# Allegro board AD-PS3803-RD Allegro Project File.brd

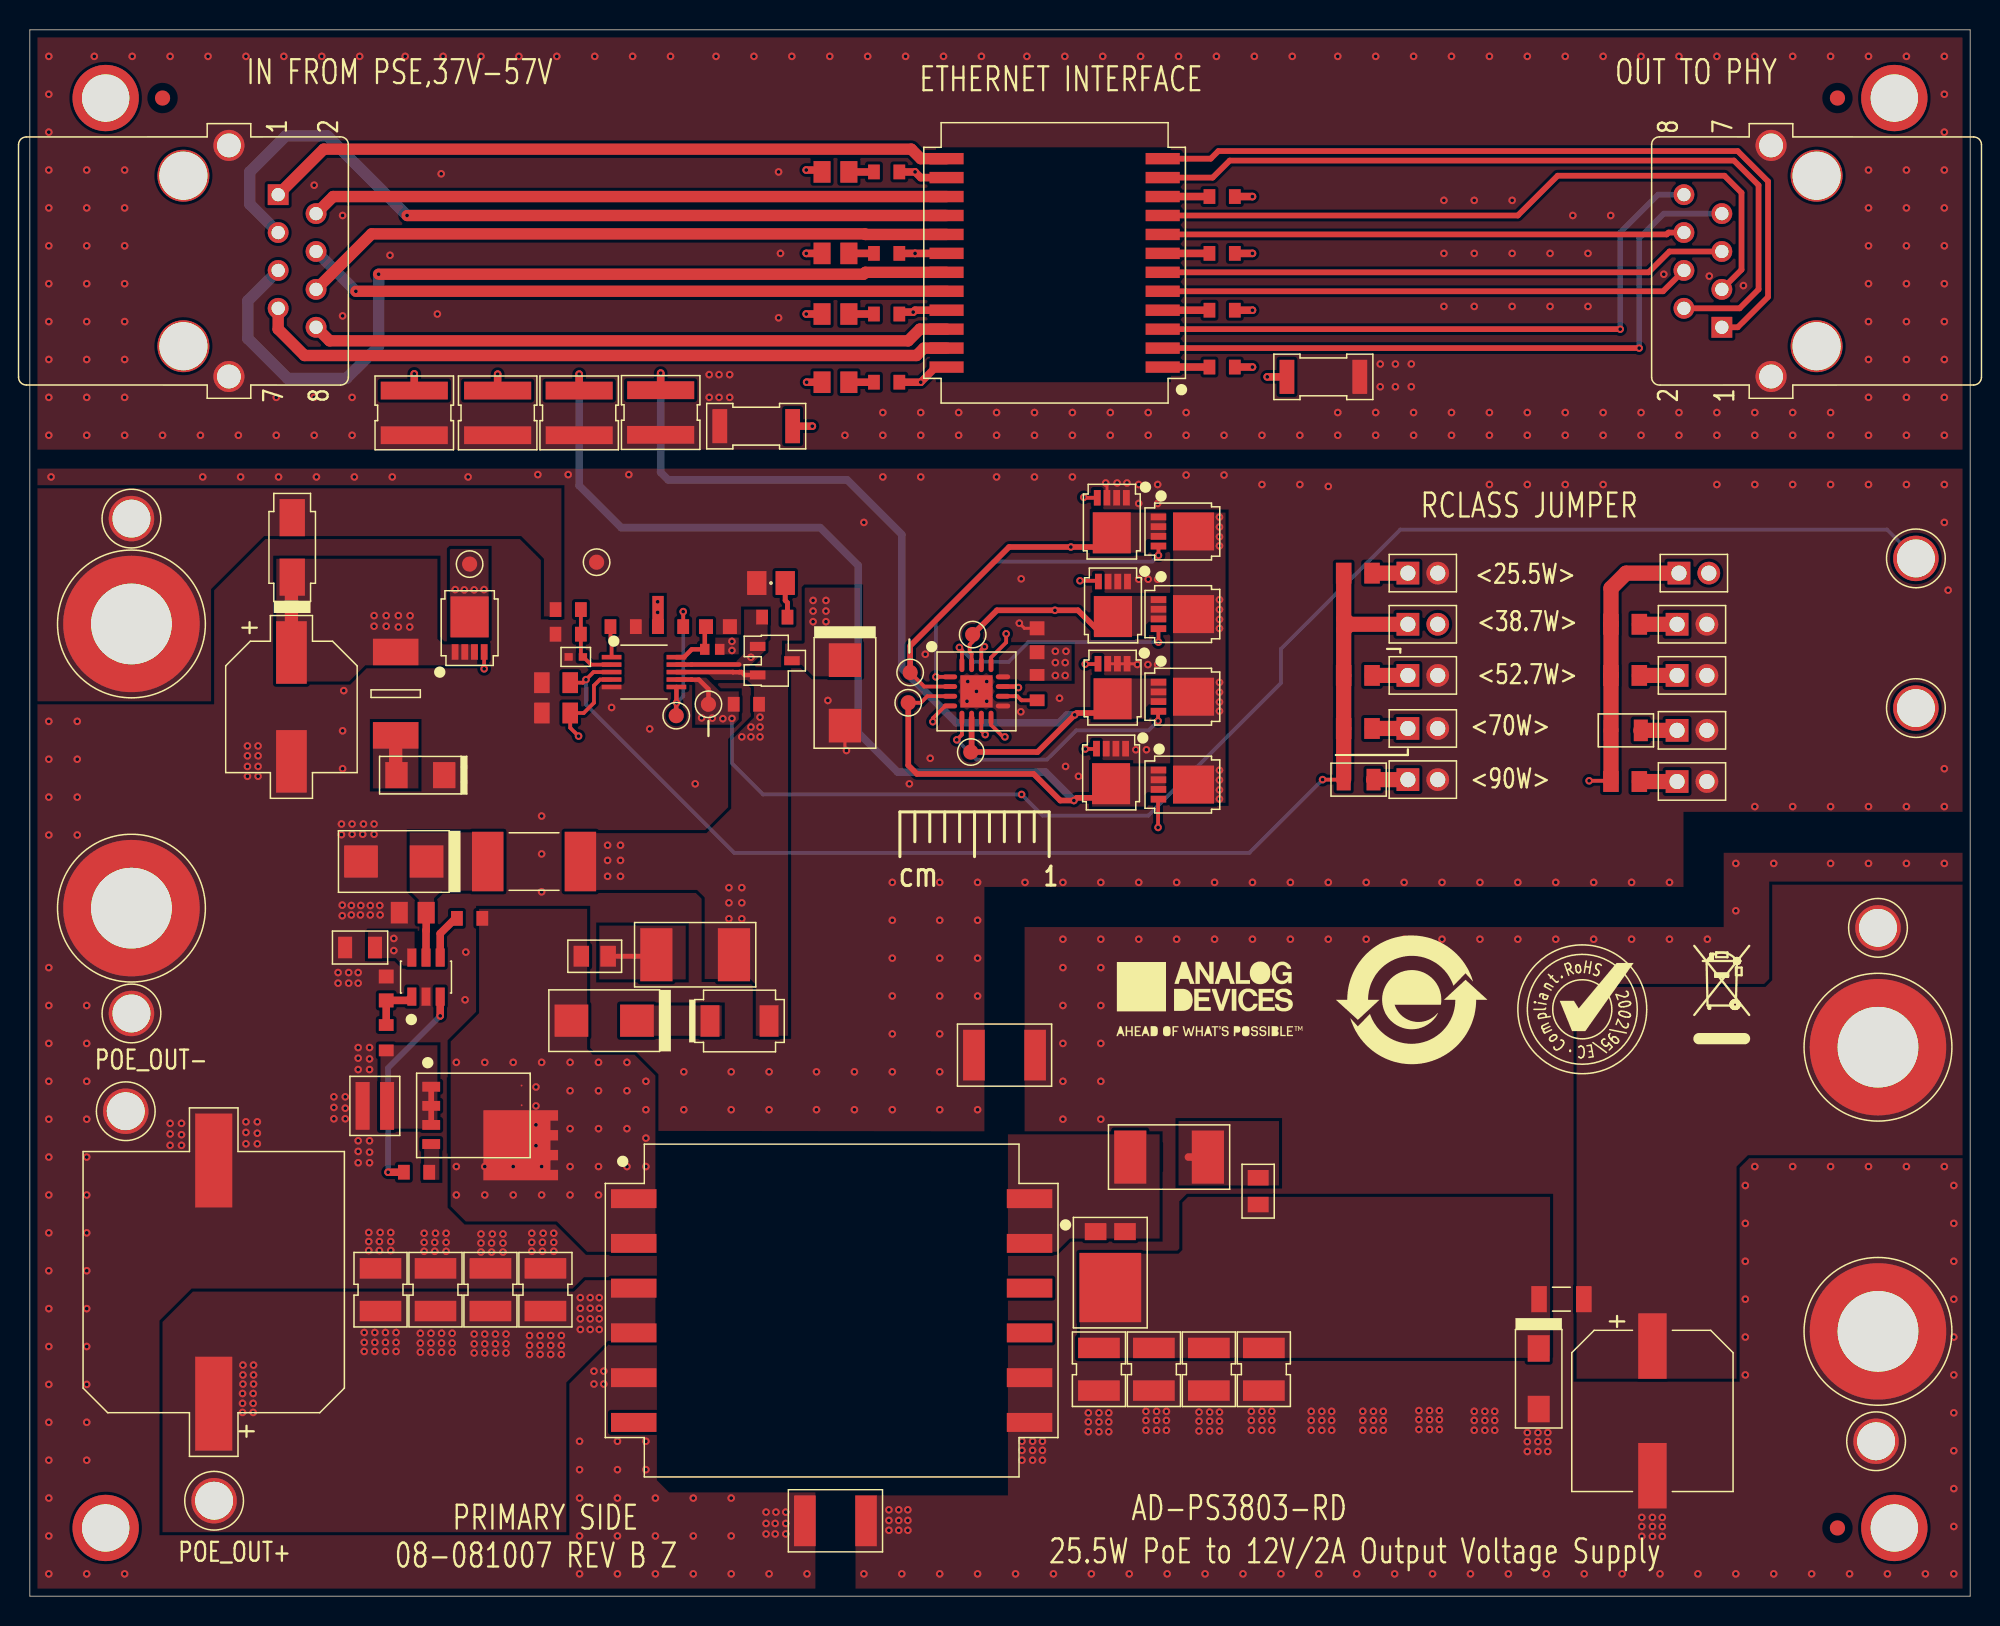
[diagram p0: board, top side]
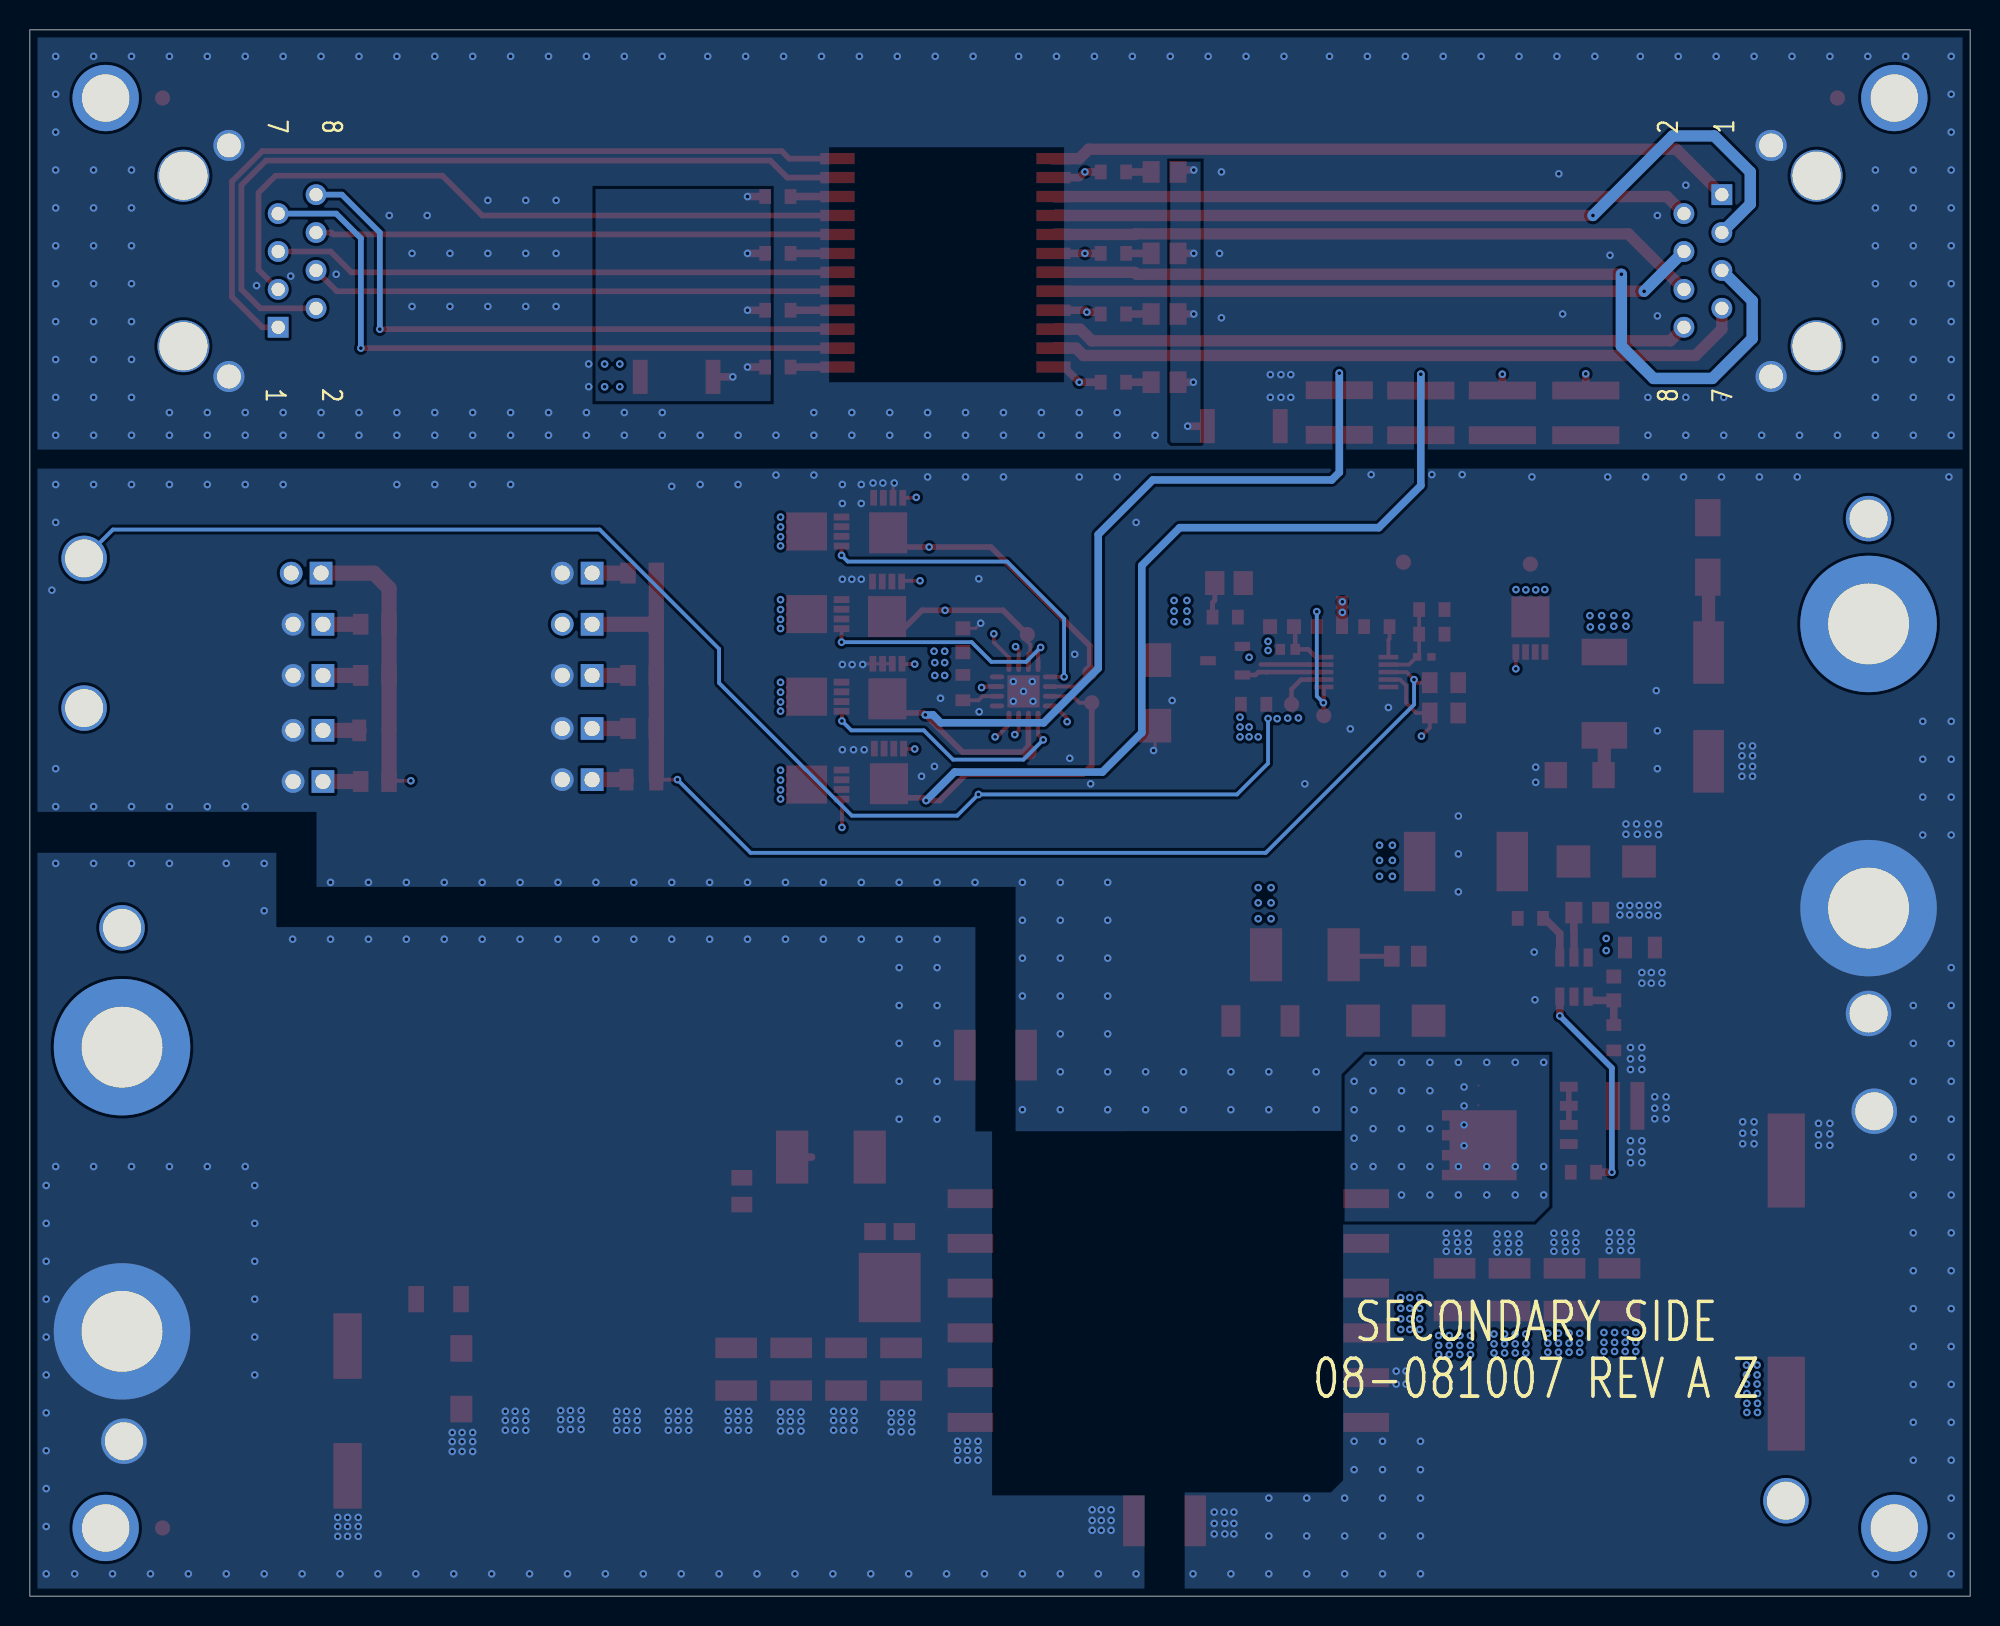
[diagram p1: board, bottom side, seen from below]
Outline 130 x 105 mm; copper layers: TOP, L2_GND, L3_PWR, BOTTOM. Coordinates in mm from the lower left corner of the outline.
Outline path: 0,105 0,0 130,0 130,105 0,105

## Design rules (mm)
constraint set DEFAULT: min track width 0.203

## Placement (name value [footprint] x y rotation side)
AUX+  575-4  [CNBANANAD312LD203]  6.81 65.17 0 top
AUX-  575-4  [CNBANANAD312LD203]  6.81 46.12 0 top
C1  0.047UF  [C0603]  67.49 64.08 90 top
C2  0.01uF  [C0402H22]  36.58 62.96 180 top
C3  0.047UF  [C0603]  46.1 65 180 top
C4  0.047uF  [C0805H60]  49.66 67.92 180 top
C5  22UF  [CPLSMSQ327H413]  17.53 59.61 270 top
C6  0.01UF  [C0805H55]  53.98 95.48 180 top
C7  0.01UF  [C0805H55]  53.98 90.01 180 top
C8  1000pF  [C1808H85]  48.67 78.43 180 top
C9  0.01UF  [C0805H55]  53.98 85.95 180 top
C10  0.01UF  [C0805H55]  53.98 81.38 180 top
C11  1000pF  [C1808H85]  86.66 81.74 0 top
C12  100uF  [CPLSMSQ669H669]  12.32 21.05 90 top
C13  10UF  [C1210H110]  23.49 20.55 90 top
C14  10UF  [C1210H110]  27.18 20.55 90 top
C15  10UF  [C1210H110]  30.86 20.55 90 top
C16  10UF  [C1210H110]  34.54 20.55 90 top
C17  1uF  [C0805]  25.65 45.82 180 top
C18  1000pF  [C0603]  23.88 40.74 90 top
C19  680PF  [C0805H30]  37.85 42.9 180 top
C20  2200pF  [C1812H100]  53.98 5.05 0 top
C21  22UF  [C1210H110]  71.63 15.21 270 top
C22  680PF  [C0805H30]  82.3 27.15 270 top
C23  22UF  [C1210H110]  75.31 15.21 270 top
C24  22UF  [C1210H110]  78.99 15.21 270 top
C25  22UF  [C1210H110]  82.68 15.21 270 top
C26  330UF  [CPLSMSQ406H500]  108.71 12.42 270 top
C35  2200pF  [C1812H100]  65.3 36.27 0 top
D1  SMBJ58A  [DO214AA_A]  54.61 60.55 270 top
D2  B1100-13-F  [SMA-2]  17.58 70.3 90 top
D3  SMBJ58A  [DO214AA_A]  24.38 49.25 180 top
D4  SMBJ28A-Q  [DO214AAH96]  47.55 38.56 0 top
D5  SDT5H100SB-13  [DO214AA_A]  38.48 38.58 180 top
D6  FSV1060V  [TO-277]  72.39 21.69 270 top
D7  CMZ5928B TR13 PBFREE  [DO214AC-2]  101.09 14.58 270 top
DS1  SML-LX1206GW-TR  [LEDSML126W63H43]  26.16 55.04 180 top
JP9  M22-2010205  [CNHDR1X2H207]  92.33 68.58 0 top
JP10  M22-2010205  [CNHDR1X2H207]  110.49 68.58 0 top
JP11  M22-2010205  [CNHDR1X2H207]  92.33 65.15 0 top
JP12  M22-2010205  [CNHDR1X2H207]  110.36 65.15 0 top
JP13  M22-2010205  [CNHDR1X2H207]  92.33 61.72 0 top
JP14  M22-2010205  [CNHDR1X2H207]  110.36 61.72 0 top
JP15  M22-2010205  [CNHDR1X2H207]  92.33 58.17 0 top
JP16  M22-2010205  [CNHDR1X2H207]  110.36 58.04 0 top
JP17  M22-2010205  [CNHDR1X2H207]  92.33 54.74 0 top
JP18  M22-2010205  [CNHDR1X2H207]  110.36 54.61 0 top
NOREF  -  []  78.74 40 0 top
NOREF#2  -  [unnamed#2]  5.08 4.57 0 top
NOREF#3  -  [unnamed#2]  124.92 100.43 0 top
NOREF#4  -  []  130 0 90 top
NOREF#5  -  [unnamed#2]  124.92 4.57 0 top
NOREF#6  -  []  35.18 0.35 270 top
NOREF#7  -  []  130 0.02 90 top
NOREF#8  -  [unnamed#2]  8.89 100.43 0 top
NOREF#9  -  []  0 104.36 0 top
NOREF#10  -  []  -14.6 -26.83 0 top
NOREF#11  -  []  58.29 52.57 0 top
NOREF#12  -  [unnamed#2]  5.08 100.43 0 top
NOREF#13  -  []  130 105 180 top
NOREF#14  -  []  104.01 39.34 0 top
NOREF#15  -  []  -222.25 -345.85 0 top
NOREF#16  -  []  0 105 270 top
NOREF#17  -  []  69.09 112.24 0 top
NOREF#18  -  []  113.16 37.06 0 top
NOREF#19  -  []  199.39 74.97 0 top
NOREF#20  -  []  0 0 0 top
NOREF#21  -  [unnamed#2]  121.11 4.57 0 top
NOREF#22  -  []  -222.25 -345.85 0 top
NOREF#23  -  []  -222.25 -345.85 0 top
NOREF#24  -  [unnamed#2]  121.11 100.43 0 top
NOREF#25  -  []  92.58 39.98 0 top
P1  SS-7188S-A-NF  [CNBELSS-7188S-A-NF]  16.64 93.95 270 top
P2  SS-7188S-A-NF  [CNBELSS-7188S-A-NF]  113.36 85.06 90 top
PWRGD  2501-2-00-80-00-00-07-0  [CNMILLMAX2501]  126.36 69.57 270 top
Q1  PSMN075-100MSEX  [SOT1210]  77.27 65.83 270 top
Q2  PSMN075-100MSEX  [SOT1210]  72.57 66.37 180 top
Q3  PSMN075-100MSEX  [SOT1210]  77.27 71.37 270 top
Q4  PSMN075-100MSEX  [SOT1210]  72.49 71.98 180 top
Q5  PSMN075-100MSEX  [SOT1210]  77.27 54.4 270 top
Q6  PSMN075-100MSEX  [SOT1210]  72.44 55.17 180 top
Q7  PSMN075-100MSEX  [SOT1210]  77.27 60.3 270 top
Q8  PSMN075-100MSEX  [SOT1210]  72.54 60.85 180 top
Q9  SI2328DS-T1-GE3  [SOT23_B]  49.91 62.71 270 top
Q10  PSMN040-100MSEX  [SOT1210]  29.46 64.94 0 top
Q11  BSC190N12NS3GATMA1  [SON8]  29.72 32.23 270 top
R1  0  [R0603]  67.49 60.91 90 top
R2  82.5K  [R0603]  36.07 66.14 0 top
R3  20K  [R0603]  36.07 64.49 180 top
R4  0  [R0603]  39.75 65 0 top
R5  34.8  [R0805]  35.26 61.24 180 top
R6  34.8  [R0805]  35.26 59.2 180 top
R7  8.2  [R0402]  45.72 63.47 180 top
R8  3.3K  [R0603]  49.91 65.63 0 top
R9  0  [R2512H35]  33.78 49.25 180 top
R10  100K  [R0603]  48.01 59.79 180 top
R11  100K  [R0603]  42.93 65 0 top
R12  4.7K  [R2512]  24.51 60.5 270 top
R13  SD4-90  [RSMSQ173H146]  42.27 79.35 270 top
R14  SD4-90  [RSMSQ173H146]  36.8 79.32 270 top
R15  SD4-90  [RSMSQ173H146]  31.34 79.32 270 top
R16  SD4-90  [RSMSQ173H146]  25.76 79.32 270 top
R17  75  [R0603]  57.4 95.48 180 top
R18  75  [R0603]  57.4 90.01 180 top
R19  75  [R0603]  57.4 85.95 180 top
R20  75  [R0603]  57.4 81.38 180 top
R21  75  [R0603]  79.88 82.39 0 top
R22  75  [R0603]  79.88 86.2 0 top
R23  75  [R0603]  79.88 90.01 0 top
R24  75  [R0603]  79.88 93.82 0 top
R28  34.8  [R0805]  88.98 68.58 0 top
R29  140  [R0805]  88.98 61.72 0 top
R30  76.8  [R0805]  88.98 58.17 0 top
R31  49.9  [R0805H20]  89.03 54.74 0 top
R32  34.8  [R0805]  106.88 65.15 180 top
R33  46.4  [R0805]  106.88 61.72 180 top
R34  64.9  [R0805H20]  106.93 58.04 180 top
R35  118  [R0805]  106.88 54.61 180 top
R36  4K  [R0805H20]  22.12 43.48 180 top
R37  237K  [R0603]  29.46 45.44 0 top
R38  17.8  [R2512H31]  44.58 43 180 top
R39  0  [R0603]  25.91 28.42 0 top
R40  0  [R0603]  23.88 37.44 270 top
R41  0.02  [R0612]  23.11 32.86 180 top
R42  17.8  [R2512H31]  76.33 29.44 0 top
R43  0  [R1206]  102.62 19.91 0 top
T1  7490220122  [TSML720W579H346]  68.66 89.38 90 top
TP1  TESTPAD  [TPSMC40]  63.17 64.46 270 top
TP2  TESTPAD  [TPSMC40]  58.98 61.92 270 top
TP3  TESTPAD  [TPSMC40]  58.85 59.89 270 top
TP4  TESTPAD  [TPSMC40]  63.04 56.59 270 top
TP5  2501-2-00-80-00-00-07-0  [CNMILLMAX2501]  6.81 72.23 0 top
TP6  2501-2-00-80-00-00-07-0  [CNMILLMAX2501]  6.81 39.06 0 top
TP7  TESTPAD  [TPSMC40]  43.31 59.03 180 top
TP8  TESTPAD  [TPSMC40]  45.47 59.79 180 top
TP14  2501-2-00-80-00-00-07-0  [CNMILLMAX2501]  12.34 6.4 180 top
TP15  2501-2-00-80-00-00-07-0  [CNMILLMAX2501]  6.43 32.51 270 top
TP16  2501-2-00-80-00-00-07-0  [CNMILLMAX2501]  123.83 44.8 180 top
TP17  2501-2-00-80-00-00-07-0  [CNMILLMAX2501]  123.7 10.39 90 top
U1  LT4321HUF#TRPBF  [QFN16_4X4_PAD2_15X2_15]  63.42 60.65 270 top
U2  LT4275AHMS#PBF  [RM10]  41.15 61.95 270 top
U3  LT8306RS6#TRMPBF  [TSOT23_6]  26.54 41.5 0 top
UNK~T2P  2501-2-00-80-00-00-07-0  [CNMILLMAX2501]  126.36 59.53 270 top
VOUT+  575-4  [CNBANANAD312LD203]  123.83 36.8 90 top
VOUT-  575-4  [CNBANANAD312LD203]  123.83 17.75 0 top
VPORT+  TESTPAD  [TPSMC40]  29.46 69.19 0 top
VPORT-  TESTPAD  [TPSMC40]  37.97 69.31 0 top
X1  750316116  [TSML969W858H450]  53.72 19.15 0 top

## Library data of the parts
AUX+ AUX- VOUT+ VOUT- = CNTP1P: Tolerance: N/A; User Part Number: UPN; alternate symbols: (CNBANANAD312LD203); part number: CNTP1P_TH-575-4,E012555,CNBANANAD312LD203; tolerance: N/A
C1 C3 = CAP: User Part Number: UPN; Tolerance: 10; alternate symbols: (C0603); part number: CAP_SM-0.047UF,100V,10,E045169,C0603; tolerance: 10
C2 = CAP: Tolerance: 10; User Part Number: UPN; alternate symbols: (C0402H22); part number: CAP_SM-0.01UF,100V,10,E018427,C0402H22; tolerance: 10
C4 = CAP: Tolerance: 10; User Part Number: UPN; alternate symbols: (C0805H60); part number: CAP_SM-0.047UF,100V,10,E030859,C0805H60; tolerance: 10
C5 = CAPP: User Part Number: UPN; Tolerance: 20; alternate symbols: (CPLSMSQ327H413); part number: CAPP_SM-22UF,100V,20,E046045,CPLSMSQ327H413; tolerance: 20
C6 C7 C9 C10 = CAP: User Part Number: UPN; Tolerance: 10; alternate symbols: (C0805H55); part number: CAP_SM-0.01UF,500V,10,E062934,C0805H55; tolerance: 10
C8 C11 = CAP: User Part Number: UPN; Tolerance: 10; alternate symbols: (C1808H85); part number: CAP_SM-1000PF,2000V,10,E033755,C1808H85; tolerance: 10
C12 = CAPP: User Part Number: UPN; Tolerance: 20; alternate symbols: (CPLSMSQ669H669); part number: CAPP_SM-100UF,100V,20,E029775,CPLSMSQ669H669; tolerance: 20
C13-C16 = CAP: Tolerance: 10; User Part Number: UPN; alternate symbols: (C1210H110); part number: CAP_SM-10UF,75V,10,E054052,C1210H110; tolerance: 10
C17 = CAP: User Part Number: UPN; Tolerance: 10; alternate symbols: (C0805); part number: CAP_SM-1UF,100V,10,E014208,C0805; tolerance: 10
C18 = CAP: User Part Number: UPN; Tolerance: 5; alternate symbols: (C0603); part number: CAP_SM-1000PF,50V,5,E007908,C0603; tolerance: 5
C19 C22 = CAP: Tolerance: 10; User Part Number: UPN; alternate symbols: (C0805H30); part number: CAP_SM-680PF,100V,10,E065750,C0805H30; tolerance: 10
C20 C35 = CAP: Tolerance: 10; User Part Number: UPN; alternate symbols: (C1812H100); part number: CAP_SM-2200PF,2000V,10,E025550,C1812H100; tolerance: 10
C21 C23-C25 = CAP: Tolerance: 10; User Part Number: UPN; alternate symbols: (C1210H110); part number: CAP_SM-22UF,25V,10,E063473,C1210H110; tolerance: 10
C26 = CAPP: Tolerance: 20; User Part Number: UPN; alternate symbols: (CPLSMSQ406H500); part number: CAPP_SM-330UF,25V,20,E046016,CPLSMSQ406H500; tolerance: 20
D1 D3 = DIOZNR: User Part Number: UPN; Tolerance: N/A; alternate symbols: (DO214AA_A); part number: DIOZNR_SM-SMBJ58A,58V,N/A,E036067,DO214AA_A; tolerance: N/A
D2 = DIOSCHOTTKY: User Part Number: UPN; Tolerance: N/A; alternate symbols: (SMA-2); part number: DIOSCHOTTKY_SM-B1100-13-F,100V,N/A,E026567,SMA-2; tolerance: N/A
D4 = DIOZNR: User Part Number: UPN; Tolerance: N/A; alternate symbols: (DO214AAH96); part number: DIOZNR_SM-SMBJ28A-Q,28V,N/A,E065782,DO214AAH96; tolerance: N/A
D5 = DIOSCHOTTKY: User Part Number: UPN; Tolerance: N/A; alternate symbols: (DO214AA_A); part number: DIOSCHOTTKY_SM-SDT5H100SB-13,100V,N/A,E057537,DO214AA_A; tolerance: N/A
D6 = DIOSCHOTTKY_3P: User Part Number: UPN; Tolerance: N/A; alternate symbols: (TO-277); part number: DIOSCHOTTKY_3P_SM-FSV1060V,60V,N/A,E044257,TO-277; tolerance: N/A
D7 = DIOZNR: User Part Number: UPN; Tolerance: 5; alternate symbols: (DO214AC-2); part number: DIOZNR_SM-CMZ5928B TR13 PBFREE,13V,5,E051593,DO214AC-2; tolerance: 5
DS1 = DIOLED: Tolerance: N/A; User Part Number: UPN; alternate symbols: (LEDSML126W63H43); part number: DIOLED_SM-SML-LX1206GW-TR,N/A,N/A,E008009,LEDSML126W63H43; tolerance: N/A
JP9-JP18 = CN2P: Tolerance: N/A; User Part Number: UPN; alternate symbols: (CNHDR1X2H207); part number: CN2P_TH-M22-2010205,E023091,CNHDR1X2H207; tolerance: N/A
P1 P2 = CN8P_2PSHLD: User Part Number: UPN; Tolerance: N/A; alternate symbols: (CNBELSS-7188S-A-NF); part number: CN8P_2PSHLD_TH-SS-7188S-A-NF,E053731,CNBELSS-7188S-A-NF; tolerance: N/A
PWRGD TP5 TP6 TP14-TP17 UNK~T2P = CNTP1P: User Part Number: UPN; Tolerance: N/A; alternate symbols: (CNMILLMAX2501); part number: CNTP1P_TH-2501-2-00-80-00-00-07-0,E031108,CNMILLMAX2501; tolerance: N/A
Q1-Q8 = TRANNMOSFET_V15: Tolerance: N/A; User Part Number: UPN; alternate symbols: (SOT1210); part number: TRANNMOSFET_V15_SM-PSMN075-100MSEX,E033196,SOT1210; tolerance: N/A
Q9 = TRANNMOSFET_V8: User Part Number: UPN; Tolerance: N/A; alternate symbols: (SOT23_B); part number: TRANNMOSFET_V8_SM-SI2328DS-T1-GE3,E051884,SOT23_B; tolerance: N/A
Q10 = TRANNMOSFET_V15: Tolerance: N/A; User Part Number: UPN; alternate symbols: (SOT1210); part number: TRANNMOSFET_V15_SM-PSMN040-100MSEX,E033197,SOT1210; tolerance: N/A
Q11 = TRANNMOSFET8P: Tolerance: N/A; User Part Number: UPN; alternate symbols: (SON8); part number: TRANNMOSFET8P_SM-BSC190N12NS3GATMA1,E063778,SON8; tolerance: N/A
R1 R4 R39 R40 = RES: User Part Number: UPN; Tolerance: JUMPER; alternate symbols: (R0603); part number: RES_SM-0,E007502,1/10W,JUMPER,R0603; tolerance: JUMPER
R2 = RES: User Part Number: UPN; Tolerance: 1; alternate symbols: (R0603); part number: RES_SM-82.5K,E045363,1/10W,1,R0603; tolerance: 1
R3 = RES: User Part Number: UPN; Tolerance: 1; alternate symbols: (R0603); part number: RES_SM-20K,E044318,1/10W,1,R0603; tolerance: 1
R5 R6 R28 R32 = RES: User Part Number: UPN; Tolerance: 1; alternate symbols: (R0805); part number: RES_SM-34.8,E050761,1/8W,1,R0805; tolerance: 1
R7 = RES: User Part Number: UPN; Tolerance: 5; alternate symbols: (R0402); part number: RES_SM-8.2,E057043,1/10W,5,R0402; tolerance: 5
R8 = RES: User Part Number: UPN; Tolerance: 1; alternate symbols: (R0603); part number: RES_SM-3.3K,E050689,1/10W,1,R0603; tolerance: 1
R9 = RES: User Part Number: UPN; Tolerance: JUMPER; alternate symbols: (R2512H35); part number: RES_SM-0,E050944,N/A,JUMPER,R2512H35; tolerance: JUMPER
R10 R11 = RES: User Part Number: UPN; Tolerance: 1; alternate symbols: (R0603); part number: RES_SM-100K,E010279,1/10W,1,R0603; tolerance: 1
R12 = RES: Tolerance: 1; User Part Number: UPN; alternate symbols: (R2512); part number: RES_SM-4.7K,E030605,1W,1,R2512; tolerance: 1
R13-R16 = RES: User Part Number: UPN; Tolerance: N/A; alternate symbols: (RSMSQ173H146); part number: RES_SM-SD4-90,E064608,N/A,N/A,RSMSQ173H146; tolerance: N/A
R17-R24 = RES: User Part Number: UPN; Tolerance: 1; alternate symbols: (R0603); part number: RES_SM-75,E003702,1/10W,1,R0603; tolerance: 1
R29 = RES: User Part Number: UPN; Tolerance: 1; alternate symbols: (R0805); part number: RES_SM-140,E003610,1/8W,1,R0805; tolerance: 1
R30 = RES: User Part Number: UPN; Tolerance: 1; alternate symbols: (R0805); part number: RES_SM-76.8,E045369,1/8W,1,R0805; tolerance: 1
R31 = RES: Tolerance: 1; User Part Number: UPN; alternate symbols: (R0805H20); part number: RES_SM-49.9,E039886,1/2W,1,R0805H20; tolerance: 1
R33 = RES: User Part Number: UPN; Tolerance: 1; alternate symbols: (R0805); part number: RES_SM-46.4,E003568,1/8W,1,R0805; tolerance: 1
R34 = RES: Tolerance: 1; User Part Number: UPN; alternate symbols: (R0805H20); part number: RES_SM-64.9,E064610,1/8W,1,R0805H20; tolerance: 1
R35 = RES: User Part Number: UPN; Tolerance: 1; alternate symbols: (R0805); part number: RES_SM-118,E045371,1/8W,1,R0805; tolerance: 1
R36 = RES: Tolerance: 1; User Part Number: UPN; alternate symbols: (R0805H20); part number: RES_SM-4K,E041265,1/8W,1,R0805H20; tolerance: 1
R37 = RES: User Part Number: UPN; Tolerance: 1; alternate symbols: (R0603); part number: RES_SM-237K,E044246,1/10W,1,R0603; tolerance: 1
R38 R42 = RES: User Part Number: UPN; Tolerance: 1; alternate symbols: (R2512H31); part number: RES_SM-17.8,E065749,1W,1,R2512H31; tolerance: 1
R41 = RES: User Part Number: UPN; Tolerance: 1; alternate symbols: (R0612); part number: RES_SM-0.02,E038131,1W,1,R0612; tolerance: 1
R43 = RES: User Part Number: UPN; Tolerance: 5; alternate symbols: (R1206); part number: RES_SM-0,E010093,1/4W,5,R1206; tolerance: 5
T1 = XFMR24P_V3: User Part Number: UPN; Tolerance: 2; alternate symbols: (TSML720W579H346); part number: XFMR24P_V3_SM-7490220122,E053759,TSML720W579H346; tolerance: 2
TP1-TP4 TP7 TP8 VPORT+ VPORT- = NCTESTPAD: Tolerance: N/A; User Part Number: UPN; alternate symbols: (TPSMC40); part number: NCTESTPAD_SM-TESTPAD,E019801,TPSMC40; tolerance: N/A
U1 = ICLT4321: User Part Number: UPN; Tolerance: N/A; alternate symbols: (QFN16_4X4_PAD2_15X2_15); part number: ICLT4321_SM-LT4321HUF#TRPBF,E033126,QFN16_4X4_PAD2_15X2_15; tolerance: N/A
U2 = ICLT4275: Tolerance: N/A; User Part Number: UPN; alternate symbols: (RM10); part number: ICLT4275_SM-LT4275AHMS#PBF,E033120,RM10; tolerance: N/A
U3 = ADLT8306: User Part Number: UPN; Tolerance: N/A; alternate symbols: (TSOT23_6); part number: ADLT8306_SM-LT8306RS6#TRMPBF,E063469,TSOT23_6; tolerance: N/A
X1 = XFMR12P_V21: User Part Number: UPN; Tolerance: N/A; alternate symbols: (TSML969W858H450); part number: XFMR12P_V21_SM-750316116,E064732,TSML969W858H450; tolerance: N/A

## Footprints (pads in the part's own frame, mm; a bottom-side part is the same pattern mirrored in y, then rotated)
C0402H22
  rect 0.559x0.508 smd: 1(-0.479,0) 2(0.479,0)
C0603
  rect 0.94x0.991 smd: 1(-0.8,0) 2(0.8,0)
C0805
  rect 1.143x1.448 smd: 1(-0.9,0) 2(0.9,0)
C0805H30
  rect 1.041x1.397 smd: 1(-0.9,0) 2(0.9,0)
C0805H55
  rect 1.143x1.448 smd: 1(-0.9,0) 2(0.9,0)
C0805H60
  rect 1.295x1.6 smd: 1(-0.953,0) 2(0.953,0)
C1210H110
  rect 1.372x2.794 smd: 1(-1.431,0) 2(1.431,0)
C1808H85
  rect 0.991x2.286 smd: 1(-2.44,0) 2(2.44,0)
C1812H100
  rect 1.448x3.404 smd: 1(-2.05,0) 2(2.05,0)
CNBANANAD312LD203
  round 9.144 hole 5.41: 1(0,0)
CNBELSS-7188S-A-NF
  round 3.48 hole 3.226 unplated: (-1.27,-6.35) (10.16,-6.35)
  rect 1.397x1.397 hole 0.889: 1(0,0)
  round 1.397 hole 0.889: 2(1.27,2.54) 3(2.54,0) 4(3.81,2.54) 5(5.08,0) 6(6.35,2.54) 7(7.62,0) 8(8.89,2.54)
  round 2.083 hole 1.6: 9(-3.3,-3.3) 10(12.19,-3.3)
CNHDR1X2H207
  rect 1.524x1.524 hole 1.016: 1(0,0)
  round 1.524 hole 1.016: 2(2,0)
CNMILLMAX2501
  round 3.048 hole 2.54: 1(0,0)
CPLSMSQ327H413
  rect 4.191x2.057 smd: N(3.65,0) P(-3.65,0)
CPLSMSQ406H500
  rect 4.394x1.905 smd: N(4.347,0) P(-4.347,0)
CPLSMSQ669H669
  rect 6.299x2.489 smd: N(8.15,0) P(-8.15,0)
DO214AA_A
  rect 2.261x2.159 smd: A(2.197,0) C(-2.197,0)
DO214AAH96
  rect 1.27x2.108 smd: A(1.98,0) C(-1.98,0)
DO214AC-2
  rect 1.778x1.473 smd: A(2.032,0) C(-2.032,0)
LEDSML126W63H43
  rect 1.499x1.753 smd: A(1.6,0) C(-1.6,0)
QFN16_4X4_PAD2_15X2_15
  oval 0.33x0.965 smd: 1(-0.975,-1.777) 2(-0.325,-1.777) 3(0.325,-1.777) 4(0.975,-1.777) 9(0.975,1.777) 10(0.325,1.777) 11(-0.325,1.777) 12(-0.975,1.777)
  oval 0.965x0.33 smd: 5(1.777,-0.975) 6(1.777,-0.325) 7(1.777,0.325) 8(1.777,0.975) 13(-1.777,0.975) 14(-1.777,0.325) 15(-1.777,-0.325) 16(-1.777,-0.975)
  rect 2.159x2.159 smd: PAD(0,0)
R0402
  rect 0.635x0.737 smd: 1(-0.5,0) 2(0.5,0)
R0603
  rect 0.787x0.991 smd: 1(-0.85,0) 2(0.85,0)
R0612
  rect 0.94x3.2 smd: 1(-0.82,0) 2(0.82,0)
R0805
  rect 1.041x1.397 smd: 1(-0.95,0) 2(0.95,0)
R0805H20
  rect 0.94x1.448 smd: 1(-1,0) 2(1,0)
R1206
  rect 1.041x1.753 smd: 1(-1.5,0) 2(1.5,0)
R2512
  rect 1.778x3.048 smd: 1(-2.794,0) 2(2.794,0)
R2512H31
  rect 2.159x3.556 smd: 1(-2.6,0) 2(2.6,0)
R2512H35
  rect 2.108x3.988 smd: 1(-3.104,0) 2(3.104,0)
RM10
  rect 0.305x1.321 smd: 1(-1,-2.171) 2(-0.5,-2.171) 3(0,-2.171) 4(0.5,-2.171) 5(1,-2.171) 6(1,2.171) 7(0.5,2.171) 8(0,2.171) 9(-0.5,2.171) 10(-1,2.171)
RSMSQ173H146
  rect 1.194x4.496 smd: 1(-1.497,0) 2(1.497,0)
SMA-2
  rect 2.489x1.702 smd: A(1.995,0) C(-1.995,0)
SON8
  rect 0.66x1.194 smd: 1(-1.92,-2.828) 2(-0.64,-2.828) 3(0.64,-2.828) 4(1.92,-2.828)
  custom 1.175x1.175 smd: 5(2,3.171)
  round 0.127 smd: 6(0.678,3.211) 7(-0.68,3.236) 8(-2.002,3.223)
SOT23_B
  rect 0.61x1.041 smd: 1(-0.958,-1.15) 2(0.958,-1.15) 3(0,1.15)
SOT1210
  rect 0.457x1.041 smd: 1(-0.975,-1.65) 2(-0.325,-1.65) 3(0.325,-1.65) 4(0.975,-1.65)
  round 0.127 smd: 5(0.975,1.65) 6(0.325,1.65) 7(-0.325,1.65) 8(-0.975,1.65)
TO-277
  rect 1.143x1.448 smd: 1(-2.75,-0.985) 2(-2.75,0.985)
  rect 4.648x4.14 smd: 3(1,0)
TPSMC40
  round 1.016 smd: 1(0,0)
TSML720W579H346
  rect 0.762x2.286 smd: 1(-6.985,-7.24) 2(-5.715,-7.24) 3(-4.445,-7.24) 4(-3.175,-7.24) 5(-1.905,-7.24) 6(-0.635,-7.24) 7(0.635,-7.24) 8(1.905,-7.24) 9(3.175,-7.24) 10(4.445,-7.24) 11(5.715,-7.24) 12(6.985,-7.24) 13(6.985,7.24) 14(5.715,7.24) 15(4.445,7.24) 16(3.175,7.24) 17(1.905,7.24) 18(0.635,7.24) 19(-0.635,7.24) 20(-1.905,7.24) 21(-3.175,7.24) 22(-4.445,7.24) 23(-5.715,7.24) 24(-6.985,7.24)
TSML969W858H450
  rect 3.048x1.27 smd: 1(-13.26,7.5) 2(-13.26,4.5) 3(-13.26,1.5) 4(-13.26,-1.5) 5(-13.26,-4.5) 6(-13.26,-7.5) 7(13.26,-7.5) 8(13.26,-4.5) 9(13.26,-1.5) 10(13.26,1.5) 11(13.26,4.5) 12(13.26,7.5)
TSOT23_6
  rect 0.61x1.219 smd: 1(-0.95,-1.31) 2(0,-1.31) 3(0.95,-1.31) 4(0.95,1.31) 5(0,1.31) 6(-0.95,1.31)
unnamed#2
  round 4.445 hole 3.175 unplated: (0,0)

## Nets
GND_EARTH: C8.2(N2) C11.2(N2) P1.9 P1.10 P2.9 P2.10 R13.2(N2) R14.2(N2) R15.2(N2) R16.2(N2)
GND_ISO: C20.2(N2) C21.2(N2) C23.2(N2) C24.2(N2) C25.2(N2) C26.N(N2) C35.2(N2) D7.A(P) TP17.1(N1) VOUT-.1(N1) X1.7 X1.8
PGND: AUX-.1(N1) C1.2(N2) C2.2(N2) C3.1 C4.2(N2) C5.N(N2) C12.N(N2) C13.2(N2) C14.2(N2) C15.2(N2) C16.2(N2) C17.2(N2) C18.2(N2) C20.1 C35.1 D1.A(P) D3.A(P) DS1.C JP9.2(N2) JP12.2(N2) JP13.2(N2) JP14.2(N2) JP15.2(N2) JP16.2(N2) JP17.2(N2) JP18.2(N2) Q2.1 Q2.2 Q2.3(S3) Q4.1 Q4.2 Q4.3(S3) Q6.1 Q6.2 Q6.3(S3) Q8.1 Q8.2 Q8.3(S3) R3.2(N2) R4.2(N2) R5.2(N2) R6.2(N2) R36.2(N2) R41.2(N2) TP6.1(N1) TP15.1(N1) U1.9 U1.PAD U2.5 U3.2 VPORT-.1(N1) X1.5
BG12: Q2.4 U1.14
BG36: Q4.4 U1.13
BG45: Q6.4 U1.8
BG78: Q8.4 U1.7
DATA1: Q1.1 Q1.2 Q1.3(S3) Q2.5 Q2.6 Q2.7 Q2.8 R16.1 R17.1 T1.14 TP1.1(N1) U1.15
DATA2: Q3.1 Q3.2 Q3.3(S3) Q4.5 Q4.6 Q4.7 Q4.8 R15.1 R18.1 T1.18 TP2.1(N1) U1.2
POE_OUT+: C5.P C12.P C13.1 C14.1 C15.1 C16.1 D2.C D4.A(P) Q9.2(S) Q10.1 Q10.2 Q10.3(S3) R9.1 R10.1 R11.1 R12.1 R38.1 TP14.1(N1) U2.8 X1.3 X1.4
PWRGD: PWRGD.1(N1) R10.2(N2) R36.1 TP8.1(N1) U1.11 U2.7 U3.6
RCLASS: JP11.1 R5.1 R28.1 R29.1 R30.1 R31.1 U2.3
RCLASS++: JP10.1 R6.1 R32.2(N2) R33.2(N2) R34.2(N2) R35.2(N2) U2.4
SPARE1: Q5.1 Q5.2 Q5.3(S3) Q6.5 Q6.6 Q6.7 Q6.8 R14.1 R19.1 T1.21 TP3.1(N1) U1.3
SPARE2: Q7.1 Q7.2 Q7.3(S3) Q8.5 Q8.6 Q8.7 Q8.8 R13.1 R20.1 T1.24 TP4.1(N1) U1.6
TG12: Q1.4 U1.16
TG36: Q3.4 U1.1
TG45: Q5.4 U1.4
TG78: Q7.4 U1.5(TG78)
UNNAMED_3_CAP_I58_N1: C6.1 R17.2(N2)
UNNAMED_3_CAP_I58_N2: C6.2(N2) C7.2(N2) C8.1 C9.2(N2) C10.2(N2)
UNNAMED_3_CAP_I62_N1: C7.1 R18.2(N2)
UNNAMED_3_CAP_I63_N1: C9.1 R19.2(N2)
UNNAMED_3_CAP_I66_N1: C10.1 R20.2(N2)
UNNAMED_3_CAP_I72_N1: C11.1 R21.2(N2) R22.2(N2) R23.2(N2) R24.2(N2)
UNNAMED_3_CN8P2PSHLD_I51_N1: P1.1 T1.13
UNNAMED_3_CN8P2PSHLD_I51_N2: P1.2 T1.15
UNNAMED_3_CN8P2PSHLD_I51_N3: P1.3 T1.16
UNNAMED_3_CN8P2PSHLD_I51_N4: P1.4 T1.20
UNNAMED_3_CN8P2PSHLD_I51_N5: P1.5 T1.19
UNNAMED_3_CN8P2PSHLD_I51_N6: P1.6 T1.17
UNNAMED_3_CN8P2PSHLD_I51_N7: P1.7 T1.23
UNNAMED_3_CN8P2PSHLD_I51_N8: P1.8(N8) T1.22
UNNAMED_3_CN8P2PSHLD_I76_N1: P2.1 T1.12(TD4-)
UNNAMED_3_CN8P2PSHLD_I76_N2: P2.2 T1.11
UNNAMED_3_CN8P2PSHLD_I76_N3: P2.3 T1.9
UNNAMED_3_CN8P2PSHLD_I76_N4: P2.4 T1.5
UNNAMED_3_CN8P2PSHLD_I76_N5: P2.5 T1.6
UNNAMED_3_CN8P2PSHLD_I76_N6: P2.6 T1.8
UNNAMED_3_CN8P2PSHLD_I76_N7: P2.7 T1.2
UNNAMED_3_CN8P2PSHLD_I76_N8: P2.8(N8) T1.3
UNNAMED_3_ICLT4321_I6_ENN: R1.1 U1.10
UNNAMED_3_RES_I69_N1: R21.1 T1.1
UNNAMED_3_RES_I70_N1: R22.1 T1.4
UNNAMED_3_RES_I73_N1: R23.1 T1.7
UNNAMED_3_RES_I74_N1: R24.1 T1.10
UNNAMED_4_CAP_I7_N2: C3.2(N2) R7.2(N2) U2.10(VPORT)
UNNAMED_4_CAP_I43_N1: C2.1 R2.2(N2) R3.1 U2.2
UNNAMED_4_CAP_I58_N1: C4.1 R8.2(N2)
UNNAMED_4_CN2P_I91_N1: JP17.1 R31.2(N2)
UNNAMED_4_CN2P_I92_N1: JP15.1 R30.2(N2)
UNNAMED_4_CN2P_I93_N1: JP18.1 R35.1
UNNAMED_4_CN2P_I94_N1: JP16.1 R34.1
UNNAMED_4_CN2P_I97_N1: JP13.1 R29.2(N2)
UNNAMED_4_CN2P_I99_N1: JP14.1 R33.1
UNNAMED_4_CN2P_I100_N1: JP12.1 R32.1
UNNAMED_4_CN2P_I101_N1: JP9.1 R28.2(N2)
UNNAMED_4_CNTP1P_I36_N1: R11.2(N2) TP7.1(N1) U2.6 UNK~T2P.1
UNNAMED_4_DIOLED_I15_P: DS1.A(P) R12.2(N2)
UNNAMED_4_DIOSCHOTTKY_I5_P: AUX+.1(N1) D2.A(P) R2.1 TP5.1(N1)
UNNAMED_4_ICLT4275_I46_HSGATE: Q9.1 Q10.4 R8.1 U2.9
UNNAMED_4_ICLT4275_I46_IEEEUVLON: R4.1 U2.1
UNNAMED_7_ADLT8306_I16_GATE: R39.1 U3.3
UNNAMED_7_ADLT8306_I16_RFB: R37.1 U3.4
UNNAMED_7_ADLT8306_I16_SENSE: C18.1 R40.1 U3.1
UNNAMED_7_ADLT8306_I16_VIN: C17.1 D3.C R9.2(N2) U3.5(VIN)
UNNAMED_7_CAP_I31_N1: C19.1 R38.2(N2)
UNNAMED_7_CAP_I31_N2: C19.2(N2) D5.A(P) Q11.5 Q11.6 Q11.7 Q11.8 R37.2(N2) X1.1 X1.2
UNNAMED_7_CAP_I39_N1: C21.1 C22.2(N2) C23.1 C24.1 C25.1 D6.3(C) D7.C R43.1
UNNAMED_7_CAP_I61_N1: C22.1 R42.2(N2)
UNNAMED_7_CAPP_I46_N1: C26.P R43.2(N2) TP16.1(N1) VOUT+.1(N1)
UNNAMED_7_DIOSCHOTTKY3P_I36_A1: D6.1 D6.2 R42.1 X1.11 X1.12
UNNAMED_7_DIOSCHOTTKY_I29_N: D4.C D5.C
UNNAMED_7_RES_I24_N2: Q11.1 Q11.2 Q11.3(S3) R40.2(N2) R41.1
UNNAMED_7_RES_I25_N2: Q11.4 R39.2(N2)
VPORTP: C1.1 D1.C Q1.5 Q1.6 Q1.7 Q1.8 Q3.5 Q3.6 Q3.7 Q3.8 Q5.5 Q5.6 Q5.7 Q5.8 Q7.5 Q7.6 Q7.7 Q7.8 Q9.3 Q10.5 Q10.6 Q10.7 Q10.8 R1.2(N2) R7.1 U1.12 VPORT+.1(N1)

Pads without a net: JP10 2; JP11 2; X1 6 9 10

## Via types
v1: diameter 0.508, hole 0.254, TOP to BOTTOM, 932 vias

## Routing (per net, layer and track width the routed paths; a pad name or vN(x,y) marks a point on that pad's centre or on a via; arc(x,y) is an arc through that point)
GND_EARTH:
  vias: v1(1.27,103.22) v1(1.27,100.68) v1(1.27,98.14) v1(1.27,95.6) v1(1.27,93.06) v1(1.27,90.52) v1(1.27,87.98) v1(1.27,85.44) v1(1.27,82.9) v1(1.27,80.36) v1(1.27,77.82) v1(3.81,95.6) v1(3.81,93.06) v1(3.81,90.52) v1(3.81,87.98) v1(3.81,85.44) v1(3.81,82.9) v1(3.81,80.36) v1(3.81,77.82) v1(4.32,103.22) v1(6.35,95.6) v1(6.35,93.06) v1(6.35,90.52) v1(6.35,87.98) v1(6.35,85.44) v1(6.35,82.9) v1(6.35,80.36) v1(6.35,77.82) v1(6.86,103.22) v1(8.89,77.82) v1(9.4,103.22) v1(11.43,77.82) v1(11.94,103.22) v1(13.97,77.82) v1(14.48,103.22) v1(16.51,80.36) v1(16.51,77.82) v1(17.02,103.22) v1(19.05,94.59) v1(19.05,80.36) v1(19.05,77.82) v1(19.56,103.22) v1(20.95,92.55) v1(20.95,85.82) v1(21.59,80.36) v1(21.59,77.82) v1(22.1,103.22) v1(24.13,89.89) v1(25.15,103.22) v1(27.3,85.95) v1(27.56,95.35) v1(27.69,103.22) v1(30.23,103.22) v1(32.77,103.22) v1(35.31,103.22) v1(37.85,103.22) v1(40.39,103.22) v1(42.93,103.22) v1(45.52,81.89) v1(45.52,80.36) v1(45.97,103.22) v1(46.18,81.89) v1(46.18,80.36) v1(46.89,81.89) v1(46.89,80.36) v1(48.51,103.22) v1(50.16,95.48) v1(50.16,85.7) v1(50.29,90.01) v1(51.05,103.22) v1(53.59,103.22) v1(54.61,77.82) v1(56.13,103.22) v1(57.15,79.35) v1(57.15,77.82) v1(58.67,103.22) v1(59.69,79.35) v1(59.69,77.82) v1(61.21,103.22) v1(62.23,79.35) v1(62.23,77.82) v1(63.75,103.22) v1(64.77,79.35) v1(64.77,77.82) v1(66.8,103.22) v1(67.31,79.35) v1(67.31,77.82) v1(69.34,103.22) v1(69.85,79.35) v1(69.85,77.82) v1(71.88,103.22) v1(72.39,79.35) v1(72.39,77.82) v1(74.42,103.22) v1(74.93,79.35) v1(74.93,77.82) v1(76.96,103.22) v1(77.47,79.35) v1(77.47,77.82) v1(79.5,103.22) v1(80.01,77.82) v1(82.04,103.22) v1(82.55,77.82) v1(84.58,103.22) v1(85.09,77.82) v1(87.63,103.22) v1(87.63,79.35) v1(87.63,77.82) v1(90.17,103.22) v1(90.17,79.35) v1(90.17,77.82) v1(90.47,82.6) v1(90.47,81.07) v1(91.49,82.6) v1(91.49,81.07) v1(92.56,82.6) v1(92.56,81.08) v1(92.71,103.22) v1(92.71,79.35) v1(92.71,77.82) v1(94.74,93.57) v1(94.74,90.01) v1(94.74,86.46) v1(95.25,103.22) v1(95.25,79.35) v1(95.25,77.82) v1(96.77,93.57) v1(96.77,90.01) v1(96.77,86.46) v1(97.79,103.22) v1(97.79,79.35) v1(97.79,77.82) v1(99.31,93.57) v1(99.31,90.01) v1(99.31,86.46) v1(100.33,103.22) v1(100.33,79.35) v1(100.33,77.82) v1(101.85,90.01) v1(101.85,86.46) v1(102.87,103.22) v1(102.87,79.35) v1(102.87,77.82) v1(103.38,92.55) v1(104.39,90.01) v1(104.39,86.46) v1(105.41,103.22) v1(105.41,79.35) v1(105.41,77.82) v1(105.92,92.55) v1(107.95,103.22) v1(107.95,79.35) v1(107.95,77.82) v1(109.47,88.62) v1(110.49,103.22) v1(110.49,79.35) v1(110.49,77.82) v1(112.52,88.49) v1(113.03,103.22) v1(113.03,79.35) v1(113.03,77.82) v1(114.81,87.86) v1(115.57,103.22) v1(115.57,79.35) v1(115.57,77.82) v1(118.11,103.22) v1(118.11,79.35) v1(118.11,77.82) v1(120.65,103.22) v1(120.65,79.35) v1(120.65,77.82) v1(123.19,103.22) v1(123.19,95.6) v1(123.19,93.06) v1(123.19,90.52) v1(123.19,87.98) v1(123.19,85.44) v1(123.19,82.9) v1(123.19,80.36) v1(123.19,77.82) v1(125.73,103.22) v1(125.73,95.6) v1(125.73,93.06) v1(125.73,90.52) v1(125.73,87.98) v1(125.73,85.44) v1(125.73,82.9) v1(125.73,80.36) v1(125.73,77.82) v1(128.27,103.22) v1(128.27,100.68) v1(128.27,98.14) v1(128.27,95.6) v1(128.27,93.06) v1(128.27,90.52) v1(128.27,87.98) v1(128.27,85.44) v1(128.27,82.9) v1(128.27,80.36) v1(128.27,77.82)
GND_ISO:
  vias: v1(55.88,1.5) v1(57.56,5.79) v1(57.56,5.08) v1(57.56,4.42) v1(58.22,5.79) v1(58.22,5.08) v1(58.22,4.42) v1(58.42,1.5) v1(58.83,5.79) v1(58.83,5.08) v1(58.83,4.42) v1(60.96,1.5) v1(63.5,1.5) v1(66.04,1.5) v1(66.47,10.39) v1(66.47,9.78) v1(66.47,9.12) v1(67.18,10.39) v1(67.18,9.78) v1(67.18,9.12) v1(67.84,10.39) v1(67.84,9.78) v1(67.84,9.12) v1(68.58,1.5) v1(69.22,44.04) v1(69.22,42.14) v1(69.22,39.6) v1(69.22,37.06) v1(69.22,34.52) v1(69.22,31.98) v1(70.92,12.29) v1(70.92,11.68) v1(70.92,11.02) v1(71.12,1.5) v1(71.63,12.29) v1(71.63,11.68) v1(71.63,11.02) v1(71.75,44.04) v1(71.75,42.14) v1(71.75,39.6) v1(71.75,37.06) v1(71.75,34.52) v1(71.75,31.98) v1(72.29,12.29) v1(72.29,11.68) v1(72.29,11.02) v1(73.66,1.5) v1(74.3,44.04) v1(74.78,12.39) v1(74.78,11.78) v1(74.78,11.12) v1(75.49,12.39) v1(75.49,11.78) v1(75.49,11.12) v1(76.15,12.39) v1(76.15,11.78) v1(76.15,11.12) v1(76.2,1.5) v1(76.83,44.04) v1(78.33,12.34) v1(78.33,11.73) v1(78.33,11.07) v1(78.74,1.5) v1(79.04,12.34) v1(79.04,11.73) v1(79.04,11.07) v1(79.38,44.04) v1(79.71,12.34) v1(79.71,11.73) v1(79.71,11.07) v1(81.28,1.5) v1(81.91,44.04) v1(81.84,12.39) v1(81.84,11.78) v1(81.84,11.12) v1(82.55,12.39) v1(82.55,11.78) v1(82.55,11.12) v1(83.21,12.39) v1(83.21,11.78) v1(83.21,11.12) v1(83.82,1.5) v1(84.45,44.04) v1(85.85,12.39) v1(85.85,11.78) v1(85.85,11.12) v1(86.36,1.5) v1(86.56,12.39) v1(86.56,11.78) v1(86.56,11.12) v1(87,44.04) v1(87.22,12.39) v1(87.22,11.78) v1(87.22,11.12) v1(88.9,1.5) v1(89.31,12.39) v1(89.31,11.78) v1(89.31,11.12) v1(89.53,44.04) v1(90.02,12.39) v1(90.02,11.78) v1(90.02,11.12) v1(90.68,12.39) v1(90.68,11.78) v1(90.68,11.12) v1(91.44,1.5) v1(92.08,44.04) v1(93.07,12.44) v1(93.07,11.83) v1(93.07,11.17) v1(93.78,12.44) v1(93.78,11.83) v1(93.78,11.17) v1(93.98,1.5) v1(94.44,12.44) v1(94.44,11.83) v1(94.44,11.17) v1(94.61,44.04) v1(96.52,1.5) v1(96.77,12.39) v1(96.77,11.78) v1(96.77,11.12) v1(97.16,44.04) v1(97.49,12.39) v1(97.49,11.78) v1(97.49,11.12) v1(98.15,12.39) v1(98.15,11.78) v1(98.15,11.12) v1(99.06,1.5) v1(99.69,44.04) v1(100.33,10.97) v1(100.33,10.36) v1(100.33,9.7) v1(101.04,10.97) v1(101.04,10.36) v1(101.04,9.7) v1(101.6,1.5) v1(101.7,10.97) v1(101.7,10.36) v1(101.7,9.7) v1(102.23,44.04) v1(104.14,1.5) v1(104.77,44.04) v1(106.68,1.5) v1(107.31,44.04) v1(108,5.28) v1(108,4.67) v1(108,4.01) v1(108.71,5.28) v1(108.71,4.67) v1(108.71,4.01) v1(109.22,1.5) v1(109.37,5.28) v1(109.37,4.67) v1(109.37,4.01) v1(109.86,44.04) v1(111.76,1.5) v1(112.39,44.04) v1(114.3,49.12) v1(114.3,45.95) v1(114.3,1.5) v1(114.94,27.53) v1(114.94,24.99) v1(114.94,22.45) v1(114.94,19.91) v1(114.94,17.37) v1(114.94,14.83) v1(115.57,28.8) v1(116.84,49.12) v1(116.84,1.5) v1(118.11,28.8) v1(119.38,1.5) v1(120.65,49.12) v1(120.65,28.8) v1(121.92,1.5) v1(123.19,49.12) v1(123.19,28.8) v1(124.46,1.5) v1(125.73,49.12) v1(125.73,28.8) v1(127,1.5) v1(128.27,49.12) v1(128.27,28.8) v1(128.91,27.53) v1(128.91,24.99) v1(128.91,22.45) v1(128.91,19.91) v1(128.91,17.37) v1(128.91,14.83) v1(128.91,12.29) v1(128.91,9.75) v1(128.91,7.21) v1(128.91,4.67) v1(128.91,1.5)
PGND: length 6.1
  TOP w0.203: C1.2 66.64,64.88 v1(66.29,65.22) ; v1(74.2,62.46) 74.15,62.5 Q8.1 Q8.2 Q8.3 ; D1.A 54.61,56.79 v1(54.71,56.69) ; v1(72.09,74.62) 72.17,74.54 Q4.3
  vias: v1(1.27,58.65) v1(1.27,56.11) v1(1.27,53.57) v1(1.27,51.03) v1(1.27,42.14) v1(1.27,39.6) v1(1.27,37.06) v1(1.27,34.52) v1(1.27,31.98) v1(1.27,29.44) v1(1.27,26.9) v1(1.27,24.36) v1(1.27,21.82) v1(1.27,19.28) v1(1.27,16.74) v1(1.27,14.2) v1(1.27,11.66) v1(1.27,9.12) v1(1.27,6.58) v1(1.27,4.04) v1(1.27,1.5) v1(1.42,75.03) v1(3.17,58.65) v1(3.17,56.11) v1(3.17,53.57) v1(3.17,51.03) v1(3.81,39.6) v1(3.81,37.06) v1(3.81,34.52) v1(3.81,31.98) v1(3.81,29.44) v1(3.81,26.9) v1(3.81,24.36) v1(3.81,21.82) v1(3.81,19.28) v1(3.81,16.74) v1(3.81,14.2) v1(3.81,11.66) v1(3.81,9.12) v1(3.81,1.5) v1(6.35,1.5) v1(9.4,31.7) v1(9.4,30.98) v1(9.4,30.22) v1(10.16,31.7) v1(10.16,30.93) v1(10.16,30.22) v1(11.58,75.03) v1(14.12,75.03) v1(14.48,31.8) v1(14.48,31.09) v1(14.48,30.32) v1(14.58,56.99) v1(14.58,56.33) v1(14.58,55.62) v1(14.58,54.96) v1(15.29,56.99) v1(15.29,56.33) v1(15.29,55.62) v1(15.29,54.96) v1(15.24,31.8) v1(15.24,31.04) v1(15.24,30.32) v1(16.66,75.03) v1(19.2,75.03) v1(20.37,33.47) v1(20.37,32.76) v1(20.37,32) v1(20.65,41.8) v1(20.65,41.09) v1(20.88,51.76) v1(20.88,51.05) v1(20.93,46.33) v1(20.93,45.61) v1(20.95,58.01) v1(20.95,55.47) v1(21.03,60.7) v1(21.13,33.47) v1(21.13,32.71) v1(21.13,32) v1(21.36,41.8) v1(21.36,41.09) v1(21.59,51.76) v1(21.59,51.08) v1(21.54,46.3) v1(21.54,45.67) v1(21.74,75.03) v1(22,41.8) v1(22,41.09) v1(22,36.78) v1(22,36.06) v1(22,35.3) v1(22,30.53) v1(22,29.82) v1(22,29.05) v1(22.17,46.3) v1(22.15,45.67) v1(22.3,51.08) v1(22.35,51.76) v1(22.71,24.38) v1(22.71,23.77) v1(22.71,23.17) v1(22.81,46.3) v1(22.81,45.67) v1(22.76,36.78) v1(22.76,36.01) v1(22.76,35.3) v1(22.76,30.53) v1(22.76,29.77) v1(22.76,29.05) v1(23.06,51.76) v1(23.06,51.08) v1(23.42,23.77) v1(23.42,23.17) v1(23.44,46.3) v1(23.47,45.67) v1(23.47,24.38) v1(24.18,24.38) v1(24.18,23.77) v1(24.18,23.17) v1(24.28,75.03) v1(26.42,24.33) v1(26.42,23.72) v1(26.42,23.12) v1(27.13,23.72) v1(27.13,23.12) v1(27.18,24.33) v1(27.89,24.33) v1(27.89,23.72) v1(27.89,23.12) v1(29.11,55.57) v1(29.11,54.56) v1(29.21,43.18) v1(29.16,39.98) v1(29.36,75.03) v1(30.23,24.28) v1(30.23,23.67) v1(30.23,23.07) v1(30.99,24.28) v1(30.94,23.67) v1(30.94,23.07) v1(31.7,24.28) v1(31.7,23.67) v1(31.7,23.07) v1(33.63,24.33) v1(33.63,23.72) v1(33.63,23.12) v1(34.04,75.18) v1(34.29,52.3) v1(34.29,49.76) v1(34.29,47.22) v1(34.39,24.33) v1(34.34,23.72) v1(34.34,23.12) v1(35.1,24.33) v1(35.1,23.72) v1(35.1,23.12) v1(36.07,75.18) v1(36.83,10.39) v1(36.83,8.48) v1(36.83,6.58) v1(36.83,4.04) v1(36.83,1.5) v1(37.8,15.08) v1(37.8,14.22) v1(38.46,15.08) v1(38.46,14.22) v1(38.98,59.57) v1(39.37,10.39) v1(39.37,8.48) v1(39.37,6.58) v1(39.37,4.04) v1(39.37,1.5) v1(40.13,75.18) v1(41.27,10.39) v1(41.27,8.48) v1(41.53,58.14) v1(41.91,6.58) v1(41.91,4.04) v1(41.91,1.5) v1(43.81,35.15) v1(43.81,32.61) v1(44.45,6.58) v1(44.45,4.04) v1(44.45,1.5) v1(44.58,54.45) v1(46.99,35.15) v1(46.99,32.61) v1(46.99,6.58) v1(46.99,4.04) v1(46.99,1.5) v1(49.33,5.64) v1(49.33,4.87) v1(49.33,4.17) v1(49.53,35.15) v1(49.53,32.61) v1(49.53,1.5) v1(49.99,5.64) v1(49.94,4.87) v1(49.94,4.17) v1(50.65,5.64) v1(50.65,4.87) v1(50.65,4.17) v1(52.07,1.5) v1(52.7,35.15) v1(52.7,32.61) v1(53.47,60.04) v1(55.24,35.15) v1(55.24,32.61) v1(55.88,71.98) v1(57.15,75.03) v1(57.78,47.85) v1(57.78,45.31) v1(57.78,42.77) v1(57.78,40.23) v1(57.78,37.69) v1(57.78,35.15) v1(57.78,32.61) v1(58.93,54.45) v1(59.69,75.03) v1(59.99,63.14) v1(60.32,56.17) v1(60.96,47.85) v1(60.96,45.31) v1(60.96,42.77) v1(60.96,40.23) v1(60.96,37.69) v1(60.96,35.15) v1(60.96,32.61) v1(62.79,59.99) v1(62.84,61.31) v1(63.42,60.65) v1(63.5,47.85) v1(63.5,45.31) v1(63.5,42.77) v1(63.5,40.23) v1(63.5,32.61) v1(64.11,61.31) v1(64.11,59.99) v1(64.77,75.03) v1(66.42,68.2) v1(66.4,59.28) v1(66.67,47.85) v1(67.31,75.03) v1(68.99,60.19) v1(69.22,47.85) v1(69.39,55.62) v1(69.85,75.03) v1(70.26,54.96) v1(71.75,47.85) v1(72.85,74.62) v1(73.51,74.62) v1(74.1,56.74) v1(74.3,74.52) v1(74.3,73.25) v1(74.3,68.17) v1(74.3,47.85) v1(74.81,56.74) v1(74.93,68.17) v1(74.91,62.45) v1(75.56,74.52) v1(75.56,73.25) v1(75.56,68.17) v1(75.56,62.46) v1(75.56,56.74) v1(76.83,47.85) v1(77.47,75.16) v1(79.38,47.85) v1(80.01,75.16) v1(81.91,47.85) v1(82.55,74.52) v1(84.45,47.85) v1(85.09,74.52) v1(87,74.39) v1(87,47.85) v1(89.53,47.85) v1(92.08,47.85) v1(94.61,47.85) v1(97.16,47.85) v1(97.79,74.52) v1(99.69,47.85) v1(100.33,74.52) v1(102.23,47.85) v1(102.87,74.52) v1(104.77,47.85) v1(105.41,74.52) v1(107.31,47.85) v1(109.86,47.85) v1(113.03,74.52) v1(115.57,74.52) v1(115.57,52.93) v1(118.11,74.52) v1(118.11,52.93) v1(120.65,74.52) v1(120.65,52.93) v1(123.19,74.52) v1(123.19,52.93) v1(125.73,74.52) v1(125.73,52.93) v1(128.27,74.52) v1(128.27,71.98) v1(128.27,55.47) v1(128.27,52.93) v1(128.52,67.44)
BG12: length 12.1
  TOP w0.254: U1.14 63.75,63.44 v1(63.96,63.65) ; Q2.4 71.54,68.07 v1(70.36,68.07)
  L3_PWR w0.254: v1(63.96,63.65) 68.09,63.65 70.36,65.91 v1(70.36,68.07)
BG36: length 16.7
  TOP w0.254: U1.13 64.4,62.92 65.41,63.94 v1(65.41,64.51) ; v1(70.61,73.66) 70.64,73.63 Q4.4
  L3_PWR w0.254: v1(65.41,64.51) 65.66,64.26 67.82,64.26 69.47,65.91 69.47,68.71 70.87,70.1 70.87,73.41 v1(70.61,73.66)
BG45: length 8.2
  TOP w0.254: U1.8 64.4,58.41 65.21,57.6 v1(65.33,57.6) ; Q6.4 71.44,56.79 v1(70.71,56.79)
  L3_PWR w0.254: v1(70.71,56.79) 66.14,56.79 v1(65.33,57.6)
BG78: length 11.6
  TOP w0.254: U1.7 63.75,58.02 v1(64.01,57.76) ; Q8.4 71.54,62.48 v1(70.71,62.48)
  L3_PWR w0.254: v1(70.71,62.48) 70.71,61.06 68.2,58.55 64.8,58.55 v1(64.01,57.76)
DATA1: length 110.8
  TOP w0.254: TP1.1 63.17,63.99 62.97,63.79 62.97,63.31 63.1,63.17 U1.15
  TOP w0.381: Q2.5 70.22,66.09 v1(68.68,66.09) 64.8,66.09 TP1.1
  TOP w0.508: R17.1 v1(59.31,95.48) 59.69,95.09 T1.14 ; R16.1 v1(25.76,81.94)
  L3_PWR w0.508: v1(59.31,95.48) 58.47,94.64 38.46,94.64 v1(25.76,81.94) 25.81,81.88 25.81,73.45 26.57,72.69 63.66,72.69 68.68,67.67 v1(68.68,66.09)
DATA2: length 105.1
  TOP w0.254: U1.2 59.92,60.98 TP2.1
  TOP w0.381: Q4.5 v1(69.75,70.33) 65.61,70.33 58.98,63.7 TP2.1
  TOP w0.508: T1.18 v1(59.31,90.01) R18.1 ; R15.1 v1(31.34,81.91)
  L3_PWR w0.508: v1(69.75,70.33) 69.75,70.68 66.27,74.17 31.88,74.17 31.34,74.7 v1(31.34,81.91) 31.34,83 39.73,91.39 57.94,91.39 v1(59.31,90.01)
POE_OUT+: length 12.6
  TOP w0.203: R11.1 42.08,65.8 42.06,65.81 v1(42.06,65.95) v1(42.06,66.66)
  TOP w0.305: U2.8 47.11,61.95 47.11,61.94 47.54,61.94 47.54,61.95 47.69,61.95 47.88,61.75 Q9.2
  TOP w0.889: C5.P 17.53,68.66
  vias: v1(14.27,15.49) v1(14.27,14.83) v1(14.27,14.22) v1(14.25,13.59) v1(14.25,12.93) v1(14.25,12.32) v1(14.99,15.49) v1(14.99,14.83) v1(14.99,14.22) v1(14.96,13.59) v1(14.96,12.93) v1(14.96,12.32) v1(22.4,17.67) v1(22.4,17.01) v1(22.4,16.4) v1(23.06,65.73) v1(23.06,65.02) v1(23.11,17.67) v1(23.11,17.01) v1(23.11,16.4) v1(23.83,17.67) v1(23.83,17.01) v1(23.83,16.4) v1(23.88,65.73) v1(23.88,65.02) v1(24.54,17.67) v1(24.54,17.01) v1(24.54,16.4) v1(24.69,65.73) v1(24.69,64.97) v1(25.48,65.73) v1(25.45,64.97) v1(26.16,17.62) v1(26.16,16.96) v1(26.16,16.35) v1(26.87,17.62) v1(26.87,16.96) v1(26.87,16.35) v1(27.58,17.62) v1(27.58,16.96) v1(27.58,16.35) v1(28.3,17.62) v1(28.3,16.96) v1(28.3,16.35) v1(29.77,17.57) v1(29.77,16.91) v1(29.77,16.3) v1(30.48,17.57) v1(30.48,16.91) v1(30.48,16.3) v1(31.19,17.57) v1(31.19,16.91) v1(31.19,16.3) v1(31.9,17.57) v1(31.9,16.91) v1(31.9,16.3) v1(33.48,17.47) v1(33.48,16.81) v1(33.48,16.2) v1(34.19,17.47) v1(34.19,16.81) v1(34.19,16.2) v1(34.9,17.47) v1(34.9,16.81) v1(34.9,16.2) v1(35.61,17.47) v1(35.61,16.81) v1(35.61,16.2) v1(36.88,20.01) v1(36.88,19.3) v1(36.88,18.59) v1(36.88,17.88) v1(37.54,20.01) v1(37.54,19.3) v1(37.54,18.59) v1(37.54,17.88) v1(38.15,20.01) v1(38.15,19.3) v1(38.15,18.59) v1(38.15,17.88) v1(38.71,50.34) v1(38.71,49.32) v1(38.71,48.26) v1(39.57,50.34) v1(39.57,49.32) v1(39.57,48.26) v1(46.84,47.49) v1(46.84,46.48) v1(46.84,45.41) v1(47.7,57.6) v1(47.7,47.49) v1(47.7,46.48) v1(47.7,45.41) v1(48.31,58.26) v1(48.31,57.6) v1(48.92,58.92) v1(48.92,58.26) v1(48.92,57.6)
PWRGD: length 109
  TOP w0.305: U1.11 66.17,60.98 v1(66.23,60.91) ; TP8.1 45.47,60.8 44.83,61.44 44.34,61.44 44.33,61.45 U2.7
  L3_PWR w0.254: v1(66.45,53.74) 65.64,53.74 62.99,56.39 62.99,58.04 65.86,60.91 v1(66.23,60.91)
  BOTTOM w0.254: PWRGD.1 124.43,71.5 91.82,71.5 83.82,63.5 83.82,61.21 74.93,52.32 67.87,52.32 v1(66.45,53.74) 49.12,53.74 47.04,55.83 v1(47.04,58.84)
  vias: v1(24.38,44.09) v1(24.38,43.28) v1(45.01,58.87) v1(45.72,58.86) v1(46.43,58.82)
RCLASS: length 80.5
  TOP w0.254: R5.1 37.06,61.24 v1(37.26,61.44) 37.77,61.95 U2.3 ; R31.1 v1(86.61,54.74)
  TOP w1.016: 88.41,65.15 88.03,65.53 ; 88.41,65.15 88.03,64.77 ; 88.41,65.15 JP11.1 ; 88.03,65.53 88.03,64.77 ; 88.03,65.53 R28.1 ; R31.1 R30.1 R29.1 88.03,64.77
  BOTTOM w0.254: v1(37.26,61.44) 37.26,59.76 47.19,49.83 81.71,49.83 v1(86.61,54.74)
RCLASS++: length 100.5
  TOP w0.254: R35.2 105.88,54.66 v1(104.47,54.66) ; U2.4 38.2,61.45 37.8,61.05 37.8,59.89 37.11,59.2 R6.1 36.21,58.21 v1(36.76,57.65)
  TOP w1.016: R35.2 R34.2 R33.2 R32.2 105.93,67.56 106.95,68.58 JP10.1
  L3_PWR w0.254: v1(36.76,57.65) 38.81,57.65 42.37,61.21 53.44,61.21 63.7,50.95 100.76,50.95 v1(104.47,54.66)
SPARE1: length 105.4
  TOP w0.254: U1.3 60.13,60.33 59.69,59.89 TP3.1
  TOP w0.381: TP3.1 58.85,55.7 59.43,55.12 67.26,55.12 69.04,53.34 v1(69.95,53.34) 70.13,53.52 Q6.5
  TOP w0.508: R14.1 v1(36.8,81.91) ; T1.21 59.31,86.2 v1(59.18,86.08) 58.38,86.08 R19.1
  L3_PWR w0.508: v1(36.8,81.91) 36.8,82.17 39.17,84.53 57.63,84.53 v1(59.18,86.08)
  BOTTOM w0.508: v1(36.8,81.91) 36.8,74.45 39.62,71.63 52.96,71.63 55.5,69.09 55.5,57.88 58.14,55.24 68.04,55.24 v1(69.95,53.34)
SPARE2: length 81.7
  TOP w0.381: Q8.5 70.13,59.2 v1(70,59.08) 67.51,56.59 TP4.1 63.1,56.64 U1.6
  TOP w0.508: T1.24 60.71,82.39 v1(59.69,81.38) R20.1 ; R13.1 v1(42.27,81.99)
  L3_PWR w0.508: v1(42.27,81.99) 42.93,82.65 58.42,82.65 v1(59.69,81.38)
  BOTTOM w0.508: v1(42.27,81.99) 42.27,75.34 42.77,74.83 54.76,74.83 58.42,71.17 58.42,62.2 62.07,58.55 68.96,58.55 69.49,59.08 v1(70,59.08)
TG12: length 16.4
  TOP w0.254: Q1.4 v1(75.62,63.95) ; U1.16 62.45,63.43 v1(62.28,63.6)
  BOTTOM w0.254: v1(75.62,63.95) 66.9,63.95 65.58,62.63 63.25,62.63 v1(62.28,63.6)
TG36: length 22.1
  TOP w0.254: v1(60.71,61.63) U1.1 ; Q3.4 v1(75.62,69.77)
  BOTTOM w0.254: v1(75.62,69.77) 75.2,69.36 64.53,69.36 60.71,65.53 v1(60.71,61.63)
TG45: length 22.4
  TOP w0.254: v1(75.59,51.53) 75.59,53.4 Q5.4 ; U1.4 61.33,59.68 60.5,58.85 v1(60.5,58.62)
  L3_PWR w0.254: v1(75.59,51.53) 66.32,51.53 60.5,57.35 v1(60.5,58.62)
TG78: length 17.4
  TOP w0.254: v1(62.1,57.4) 62.45,57.75 U1.5 ; v1(75.59,58.67) 75.59,59.29 Q7.4
  BOTTOM w0.254: v1(62.1,57.4) 63.43,56.08 68.14,56.08 70.1,58.04 74.96,58.04 v1(75.59,58.67)
UNNAMED_3_CAP_I58_N1: length 1.7
  TOP w0.508: R17.2 C6.1
UNNAMED_3_CAP_I58_N2: length 5.6
  TOP w0.508: C9.2 v1(52.02,85.95) ; C8.1 v1(52.43,78.43) ; C10.2 v1(52.05,81.38) ; v1(52.02,95.6) 52.95,95.6 C6.2 ; v1(52.02,90.01) C7.2
UNNAMED_3_CAP_I62_N1: length 1.7
  TOP w0.508: C7.1 R18.2
UNNAMED_3_CAP_I63_N1: length 1.7
  TOP w0.508: R19.2 C9.1
UNNAMED_3_CAP_I66_N1: length 1.7
  TOP w0.508: C10.1 R20.2
UNNAMED_3_CAP_I72_N1: length 6
  TOP w0.508: R23.2 v1(81.91,90.01) ; R24.2 v1(81.91,93.82) ; R22.2 v1(81.91,86.2) ; R21.2 v1(81.91,82.39) ; C11.1 v1(82.91,81.74)
UNNAMED_3_CN8P2PSHLD_I51_N1: length 46.3
  TOP w0.762: P1.1 19.69,97 59.06,97 59.69,96.36 T1.13
UNNAMED_3_CN8P2PSHLD_I51_N2: length 42.7
  TOP w0.762: 19.18,92.68 20.32,93.82 T1.15
UNNAMED_3_CN8P2PSHLD_I51_N3: length 54.7
  TOP w0.762: T1.16 v1(25.27,92.55)
  BOTTOM w0.762: v1(25.27,92.55) 19.94,97.89 17.14,97.89 14.73,95.48 14.73,93.32 P1.3
UNNAMED_3_CN8P2PSHLD_I51_N4: length 43.3
  TOP w0.762: v1(21.84,87.47) T1.20
  BOTTOM w0.762: v1(21.84,87.47) 19.18,90.14
UNNAMED_3_CN8P2PSHLD_I51_N5: length 59.1
  TOP w0.762: v1(23.37,88.62) 55.85,88.62 55.98,88.74 T1.19
  BOTTOM w0.762: P1.5 14.61,86.84 14.61,84.3 17.27,81.63 21.21,81.63 23.37,83.79 v1(23.37,88.62)
UNNAMED_3_CN8P2PSHLD_I51_N6: length 43.8
  TOP w0.762: 19.18,87.6 22.9,91.32 55.94,91.32 55.98,91.28 T1.17
UNNAMED_3_CN8P2PSHLD_I51_N7: length 47.1
  TOP w0.762: P1.7 16.64,84.93 18.4,83.17 59.41,83.17 59.9,83.66 T1.23
UNNAMED_3_CN8P2PSHLD_I51_N8: length 42.9
  TOP w0.762: 19.18,85.06 20.08,84.15 58.85,84.15 59.63,84.93 T1.22
UNNAMED_3_CN8P2PSHLD_I76_N1: length 53.3
  TOP w0.381: T1.12 79.12,96.36 79.63,96.87 114.43,96.87 116.46,94.84 116.46,87.09 114.43,85.06 P2.1
UNNAMED_3_CN8P2PSHLD_I76_N2: length 53.6
  TOP w0.381: P2.2 114.55,86.33 115.82,87.6 115.82,94.59 114.17,96.24 80.39,96.24 79.25,95.09 T1.11
UNNAMED_3_CN8P2PSHLD_I76_N3: length 47.4
  TOP w0.381: T1.9 99.69,92.55 102.36,95.22 113.54,95.22 114.68,94.08 114.68,88.92 P2.3
UNNAMED_3_CN8P2PSHLD_I76_N4: length 35.5
  TOP w0.381: P2.4 109.43,87.47 T1.5
UNNAMED_3_CN8P2PSHLD_I76_N5: length 38
  TOP w0.381: T1.6 108.46,88.74 109.85,90.14 P2.5
UNNAMED_3_CN8P2PSHLD_I76_N6: length 35
  TOP w0.381: P2.6 109.79,91.41 109.67,91.28 T1.8
UNNAMED_3_CN8P2PSHLD_I76_N7: length 45.5
  TOP w0.381: v1(107.82,83.66) T1.2
  BOTTOM w0.381: P2.7 109.47,92.68 107.82,91.03 v1(107.82,83.66)
UNNAMED_3_CN8P2PSHLD_I76_N8: length 42.5
  TOP w0.381: T1.3 v1(106.55,84.93)
  BOTTOM w0.381: v1(106.55,84.93) 106.55,91.41 109.09,93.95 P2.8
UNNAMED_3_ICLT4321_I6_ENN: length 2.4
  TOP w0.254: R1.1 66.45,60.06 66.44,60.06 66.43,60.07 66.17,60.33 66.01,60.33 U1.10
UNNAMED_3_RES_I69_N1: length 3.1
  TOP w0.508: T1.1 R21.1
UNNAMED_3_RES_I70_N1: length 3.1
  TOP w0.508: T1.4 R22.1
UNNAMED_3_RES_I73_N1: length 3.1
  TOP w0.508: T1.7 R23.1
UNNAMED_3_RES_I74_N1: length 3.1
  TOP w0.508: T1.10 R24.1
UNNAMED_4_CAP_I7_N2: length 3.7
  TOP w0.305: U2.10 43.83,62.95 44.35,63.47 R7.2 45.22,64.91 C3.2
UNNAMED_4_CAP_I43_N1: length 5.4
  TOP w0.254: U2.2 37.6,62.45 37.08,62.96 C2.1 36.92,63.1 R3.1 R2.2
UNNAMED_4_CAP_I58_N1: length 2.3
  TOP w0.33: R8.2 50.76,66.6 50.61,66.75 C4.1
UNNAMED_4_CN2P_I91_N1: length 2.3
  TOP w1.016: R31.2 JP17.1
UNNAMED_4_CN2P_I92_N1: length 2.4
  TOP w1.016: R30.2 JP15.1
UNNAMED_4_CN2P_I93_N1: length 2.5
  TOP w1.016: R35.1 JP18.1
UNNAMED_4_CN2P_I94_N1: length 2.4
  TOP w1.016: R34.1 JP16.1
UNNAMED_4_CN2P_I97_N1: length 2.4
  TOP w1.016: R29.2 JP13.1
UNNAMED_4_CN2P_I99_N1: length 2.5
  TOP w1.016: R33.1 JP14.1
UNNAMED_4_CN2P_I100_N1: length 2.5
  TOP w1.016: R32.1 JP12.1
UNNAMED_4_CN2P_I101_N1: length 2.4
  TOP w1.016: R28.2 JP9.1
UNNAMED_4_CNTP1P_I36_N1: length 101.8
  TOP w0.254: R11.2 v1(43.78,66)
  TOP w0.305: 43.31,59.86 43.31,59.89 43.32,59.9 U2.6 ; 43.31,59.86 v1(43.33,59.89) ; 43.31,59.86 TP7.1
  L3_PWR w0.254: UNK~T2P.1 118.87,59.53 115.92,56.58 108.01,56.58 100.17,48.74 63.5,48.74 51.82,60.42 43.87,60.42 v1(43.33,59.89)
  BOTTOM w0.254: v1(43.78,66) 43.78,60.33 v1(43.33,59.89)
UNNAMED_4_DIOLED_I15_P: length 2.7
  TOP w0.889: 24.51,54.99 R12.2
UNNAMED_4_ICLT4275_I46_HSGATE: length 23.5
  TOP w0.254: Q10.4 v1(30.44,62.17)
  TOP w0.305: 47.52,62.46 44.34,62.46 44.33,62.45 U2.9
  L3_PWR w0.254: v1(48.31,62.94) 47.54,62.17 v1(30.44,62.17)
UNNAMED_4_ICLT4275_I46_IEEEUVLON: length 2.1
  TOP w0.254: R4.1 38.9,64.17 38.98,64.09 U2.1
UNNAMED_7_ADLT8306_I16_GATE: length 14.3
  TOP w0.508: v1(27.49,38.9) U3.3 ; R39.1 v1(24,28.42)
  BOTTOM w0.381: v1(27.49,38.9) 24,35.41 v1(24,28.42)
UNNAMED_7_ADLT8306_I16_RFB: length 3.2
  TOP w0.508: R37.1 28.51,45.44 27.49,44.42 U3.4
UNNAMED_7_ADLT8306_I16_SENSE: length 3.5
  TOP w0.508: R40.1 C18.1 25.34,39.94 U3.1
UNNAMED_7_ADLT8306_I16_VIN: length 3
  TOP w0.508: C17.1 26.55,44.64 26.54,44.63 U3.5
UNNAMED_7_CAP_I31_N1: length 2.9
  TOP w0.33: 39.35,42.9 41.78,42.9
  TOP w0.635: 41.78,42.9 42.29,42.9
UNNAMED_7_CAP_I31_N2: length 0.1
  TOP w0.508: 30.41,45.44 R37.2
  vias: v1(28.58,35.79) v1(28.58,28.8) v1(28.58,26.9) v1(30.48,35.79) v1(30.48,28.8) v1(30.48,26.9) v1(32.38,35.79) v1(32.38,28.8) v1(32.38,26.9) v1(33.91,34.13) v1(33.91,32.86) v1(33.91,31.59) v1(33.91,30.2) v1(34.29,35.79) v1(34.29,28.8) v1(34.29,26.9) v1(36.2,35.79) v1(36.2,33.88) v1(36.2,31.34) v1(36.2,28.8) v1(36.2,26.9) v1(38.1,35.79) v1(38.1,33.88) v1(38.1,31.34) v1(38.1,28.8) v1(38.1,26.9) v1(40,35.79) v1(40,33.88) v1(40,31.34) v1(40,28.8) v1(41.27,34.52) v1(41.27,32.61) v1(41.27,30.71) v1(41.27,28.8)
UNNAMED_7_CAP_I61_N1: length 1.5
  TOP w0.508: 77.63,29.44 R42.2 79.12,29.44
UNNAMED_7_RES_I24_N2: length 2.6
  TOP w0.381: Q11.1 Q11.2 Q11.3
VPORTP:
  vias: v1(28.5,67.48) v1(29.11,67.46) v1(29.77,67.46) v1(30.43,67.48) v1(47.04,64) v1(47.04,63.39) v1(52.48,66.75) v1(52.48,66.04) v1(52.48,65.33) v1(53.34,66.75) v1(53.34,66.04) v1(53.34,65.33) v1(68.71,63.34) v1(68.71,62.58) v1(68.71,61.72) v1(69.42,63.34) v1(69.37,62.58) v1(69.37,61.72) v1(79.71,72.34) v1(79.71,71.68) v1(79.71,71.01) v1(79.71,70.41) v1(79.71,66.8) v1(79.71,66.14) v1(79.71,65.48) v1(79.71,64.87) v1(79.71,61.26) v1(79.71,60.6) v1(79.71,59.94) v1(79.71,59.33) v1(79.71,55.37) v1(79.71,54.71) v1(79.71,54.05) v1(79.71,53.44)

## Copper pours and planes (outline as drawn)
GND_EARTH on TOP: 0.51,104.49 129.46,104.49 129.49,104.46 129.49,76.86 0.51,76.86 ; 3 cut-outs
GND_EARTH on BOTTOM, L2_GND, L3_PWR: 0.51,104.49 129.46,104.49 129.49,104.46 129.49,76.86 0.51,76.86 ; 1 cut-out
GND_ISO on TOP: 103.39,19.03 103.4,18.98 103.42,18.93 103.43,18.92 103.43,14.37 107.7,14.37 107.76,14.36 109.66,14.36 109.72,14.37 114.55,14.37 114.55,28.72 115.2,29.36 129.49,29.36 129.49,0.51 55.32,0.51 55.32,6.75 65.53,6.75 65.53,16.81 68.51,16.81 68.65,16.87 68.71,17.01 68.71,18.28 68.65,18.43 68.51,18.49 65.53,18.49 65.53,19.81 68.51,19.81 68.65,19.87 68.71,20.01 68.71,21.28 68.65,21.43 68.51,21.49 65.53,21.49 65.53,22.81 68.51,22.81 68.59,22.83 68.66,22.88 68.87,22.88 69.76,23.77 70.5,23.77 70.51,23.75 70.59,23.69 70.68,23.66 72.13,23.66 72.22,23.69 72.3,23.75 72.31,23.77 72.47,23.77 72.48,23.75 72.56,23.69 72.65,23.66 74.1,23.66 74.19,23.69 74.27,23.75 74.28,23.77 75.9,23.77 75.9,28.42 75.9,28.43 75.92,28.48 75.93,28.53 75.93,30.34 75.92,30.39 75.9,30.44 75.9,30.45 75.9,31.16 66.65,31.16 66.65,44.85 113.49,44.85 113.49,49.83 129.49,49.83 129.49,47.9 116.53,47.9 116.53,41.38 116.2,41.04 105.99,41.04 103.43,38.49 103.43,20.9 103.42,20.89 103.4,20.84 103.39,20.79
GND_ISO on BOTTOM, L2_GND, L3_PWR: 129.49,49.83 129.49,0.51 65.99,0.51 65.99,0.5 55.32,0.51 55.32,6.75 65.53,6.75 65.53,31.16 66.65,31.16 66.65,44.85 113.49,44.85 113.49,49.83
PGND on TOP, BOTTOM, L2_GND, L3_PWR: 0.51,75.59 42.01,75.59 42.01,75.59 129.49,75.59 129.49,75.59 129.49,52.57 110.79,52.57 110.79,47.55 63.96,47.55 63.96,31.16 43,31.19 42.01,31.19 42.01,7.77 42.82,6.96 52.63,6.96 52.63,0.51 0.51,0.51 0.51,75.17
DATA1 on TOP (solid shape): 73.84,64.29 71.29,64.29 71.29,67.04 73.84,67.04
DATA1 on TOP: 71.27,64.36 74.78,64.36 74.78,65.12 74.98,65.33 76.15,65.33 76.15,67.05 71.27,67.05
DATA2 on TOP (solid shape): 73.77,69.91 71.22,69.91 71.22,72.65 73.77,72.65
DATA2 on TOP: 71.22,69.95 74.73,69.95 74.73,70.71 74.88,70.86 76.1,70.86 76.1,72.64 71.22,72.64
POE_OUT+ on TOP (solid shape): 42.47,64.51 41.71,64.51 41.71,67.05 42.47,67.05
POE_OUT+ on TOP: 27.3,69.54 27.3,64.18 27.69,63.8 29.97,63.8 29.97,62.4 22.48,62.4 21.39,61.31 18.54,61.31 18.53,61.28 18.49,61.26 16.56,61.26 16.52,61.28 16.51,61.31 16.51,69.54
